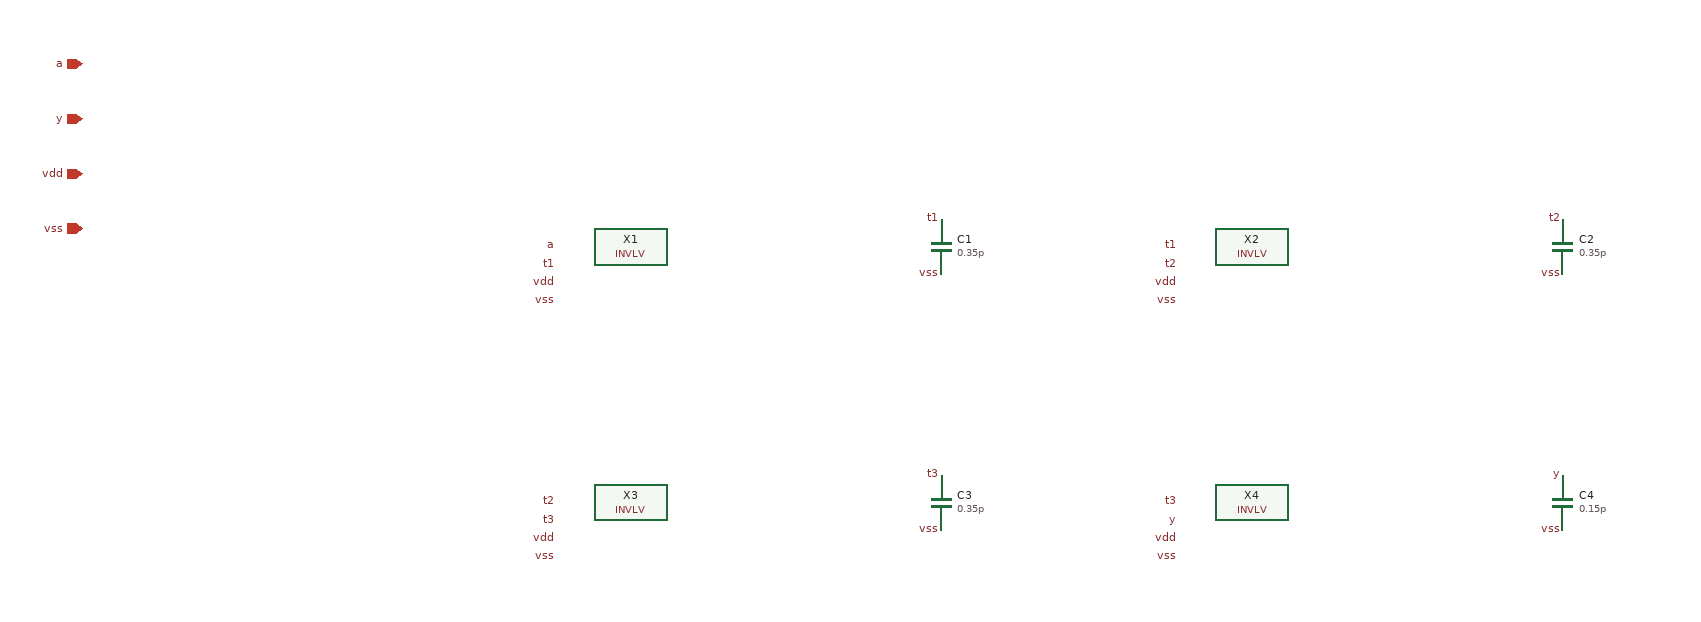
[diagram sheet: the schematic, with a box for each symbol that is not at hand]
v {xschem version=3.4.4 file_version=1.2}
G {}
K {}
V {}
S {}
E {}
C {devices/iopin.sym} -400 0 0 0 {name=p0 lab=a}
C {devices/iopin.sym} -400 60 0 0 {name=p1 lab=y}
C {devices/iopin.sym} -400 120 0 0 {name=p2 lab=vdd}
C {devices/iopin.sym} -400 180 0 0 {name=p3 lab=vss}
C {cplz_ls01/INVLV.sym} 200 200 0 0 {name=X1}
C {devices/lab_pin.sym} 120 200 0 0 {name=l1 sig_type=std_logic lab=a}
C {devices/lab_pin.sym} 120 220 0 0 {name=l2 sig_type=std_logic lab=t1}
C {devices/lab_pin.sym} 120 240 0 0 {name=l3 sig_type=std_logic lab=vdd}
C {devices/lab_pin.sym} 120 260 0 0 {name=l4 sig_type=std_logic lab=vss}
C {devices/capa.sym} 540 200 0 0 {name=C1 value=0.35p footprint=1206 m=1}
C {devices/lab_pin.sym} 540 170 0 0 {name=l5 sig_type=std_logic lab=t1}
C {devices/lab_pin.sym} 540 230 0 0 {name=l6 sig_type=std_logic lab=vss}
C {cplz_ls01/INVLV.sym} 880 200 0 0 {name=X2}
C {devices/lab_pin.sym} 800 200 0 0 {name=l7 sig_type=std_logic lab=t1}
C {devices/lab_pin.sym} 800 220 0 0 {name=l8 sig_type=std_logic lab=t2}
C {devices/lab_pin.sym} 800 240 0 0 {name=l9 sig_type=std_logic lab=vdd}
C {devices/lab_pin.sym} 800 260 0 0 {name=l10 sig_type=std_logic lab=vss}
C {devices/capa.sym} 1220 200 0 0 {name=C2 value=0.35p footprint=1206 m=1}
C {devices/lab_pin.sym} 1220 170 0 0 {name=l11 sig_type=std_logic lab=t2}
C {devices/lab_pin.sym} 1220 230 0 0 {name=l12 sig_type=std_logic lab=vss}
C {cplz_ls01/INVLV.sym} 200 480 0 0 {name=X3}
C {devices/lab_pin.sym} 120 480 0 0 {name=l13 sig_type=std_logic lab=t2}
C {devices/lab_pin.sym} 120 500 0 0 {name=l14 sig_type=std_logic lab=t3}
C {devices/lab_pin.sym} 120 520 0 0 {name=l15 sig_type=std_logic lab=vdd}
C {devices/lab_pin.sym} 120 540 0 0 {name=l16 sig_type=std_logic lab=vss}
C {devices/capa.sym} 540 480 0 0 {name=C3 value=0.35p footprint=1206 m=1}
C {devices/lab_pin.sym} 540 450 0 0 {name=l17 sig_type=std_logic lab=t3}
C {devices/lab_pin.sym} 540 510 0 0 {name=l18 sig_type=std_logic lab=vss}
C {cplz_ls01/INVLV.sym} 880 480 0 0 {name=X4}
C {devices/lab_pin.sym} 800 480 0 0 {name=l19 sig_type=std_logic lab=t3}
C {devices/lab_pin.sym} 800 500 0 0 {name=l20 sig_type=std_logic lab=y}
C {devices/lab_pin.sym} 800 520 0 0 {name=l21 sig_type=std_logic lab=vdd}
C {devices/lab_pin.sym} 800 540 0 0 {name=l22 sig_type=std_logic lab=vss}
C {devices/capa.sym} 1220 480 0 0 {name=C4 value=0.15p footprint=1206 m=1}
C {devices/lab_pin.sym} 1220 450 0 0 {name=l23 sig_type=std_logic lab=y}
C {devices/lab_pin.sym} 1220 510 0 0 {name=l24 sig_type=std_logic lab=vss}
